VERSION 5.8 ;
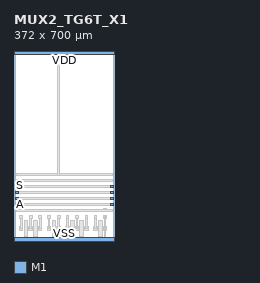
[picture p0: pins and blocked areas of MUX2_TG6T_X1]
MACRO MUX2_TG6T_X1
  CLASS CORE ;
  ORIGIN 0 0 ;
  SIZE 372 BY 700 ;
  SITE ICPS2023_5_ROW700 ;
  PIN A
    DIRECTION INPUT ;
    USE SIGNAL ;
    PORT
      LAYER M1 ;
        RECT 5 130 15 140 ;
        RECT 357 130 367 140 ;
    END
  END A
  PIN B
    DIRECTION INPUT ;
    USE SIGNAL ;
    PORT
      LAYER M1 ;
        RECT 5 152 15 162 ;
        RECT 357 152 367 162 ;
    END
  END B
  PIN S
    DIRECTION INPUT ;
    USE SIGNAL ;
    PORT
      LAYER M1 ;
        RECT 5 174 15 184 ;
        RECT 357 174 367 184 ;
    END
  END S
  PIN Y
    DIRECTION OUTPUT ;
    USE SIGNAL ;
    PORT
      LAYER M1 ;
        RECT 5 196 15 206 ;
        RECT 357 196 367 206 ;
    END
  END Y
  PIN VDD
    DIRECTION INOUT ;
    USE POWER ;
    PORT
      LAYER M1 ;
        RECT 0 688 372 700 ;
    END
  END VDD
  PIN VSS
    DIRECTION INOUT ;
    USE GROUND ;
    PORT
      LAYER M1 ;
        RECT 0 0 372 12 ;
    END
  END VSS
  OBS
    LAYER M1 ;
      RECT 20 39.5 33 52.5 ;
      RECT 55 39.5 68 52.5 ;
      RECT 90 39.5 103 52.5 ;
      RECT 37.5 16 50.5 29 ;
      RECT 37.5 63 50.5 76 ;
      RECT 37 16 51 76 ;
      RECT 72.5 16 85.5 29 ;
      RECT 72.5 63 85.5 76 ;
      RECT 72 16 86 76 ;
      RECT 23.5 46 29.5 89 ;
      RECT 21.5 84 31.5 94 ;
      RECT 21.5 130 31.5 140 ;
      RECT 58.5 46 64.5 89 ;
      RECT 56.5 84 66.5 94 ;
      RECT 56.5 196 66.5 206 ;
      RECT 93.5 46 99.5 89 ;
      RECT 91.5 84 101.5 94 ;
      RECT 91.5 152 101.5 162 ;
      RECT 39 218 49 228 ;
      RECT 74 174 84 184 ;
      RECT 123 39.5 136 52.5 ;
      RECT 158 39.5 171 52.5 ;
      RECT 140.5 16 153.5 29 ;
      RECT 140.5 63 153.5 76 ;
      RECT 140 16 154 76 ;
      RECT 126.5 46 132.5 89 ;
      RECT 124.5 84 134.5 94 ;
      RECT 124.5 218 134.5 228 ;
      RECT 161.5 46 167.5 89 ;
      RECT 159.5 84 169.5 94 ;
      RECT 159.5 240 169.5 250 ;
      RECT 142 174 152 184 ;
      RECT 191 39.5 204 52.5 ;
      RECT 226 39.5 239 52.5 ;
      RECT 261 39.5 274 52.5 ;
      RECT 208.5 16 221.5 29 ;
      RECT 208.5 63 221.5 76 ;
      RECT 208 16 222 76 ;
      RECT 243.5 16 256.5 29 ;
      RECT 243.5 63 256.5 76 ;
      RECT 243 16 257 76 ;
      RECT 194.5 46 200.5 89 ;
      RECT 192.5 84 202.5 94 ;
      RECT 192.5 130 202.5 140 ;
      RECT 229.5 46 235.5 89 ;
      RECT 227.5 84 237.5 94 ;
      RECT 227.5 196 237.5 206 ;
      RECT 264.5 46 270.5 89 ;
      RECT 262.5 84 272.5 94 ;
      RECT 262.5 152 272.5 162 ;
      RECT 210 174 220 184 ;
      RECT 245 218 255 228 ;
      RECT 294 39.5 307 52.5 ;
      RECT 329 39.5 342 52.5 ;
      RECT 311.5 16 324.5 29 ;
      RECT 311.5 63 324.5 76 ;
      RECT 311 16 325 76 ;
      RECT 297.5 46 303.5 89 ;
      RECT 295.5 84 305.5 94 ;
      RECT 295.5 218 305.5 228 ;
      RECT 332.5 46 338.5 89 ;
      RECT 330.5 84 340.5 94 ;
      RECT 330.5 108 340.5 118 ;
      RECT 313 174 323 184 ;
      RECT 10 110 362 116 ;
      RECT 10 132 362 138 ;
      RECT 10 154 362 160 ;
      RECT 10 176 362 182 ;
      RECT 10 198 362 204 ;
      RECT 10 220 362 226 ;
      RECT 10 242 362 248 ;
      RECT 332.5 3 338.5 92 ;
      RECT 161.5 242 167.5 697 ;
  END
END MUX2_TG6T_X1
